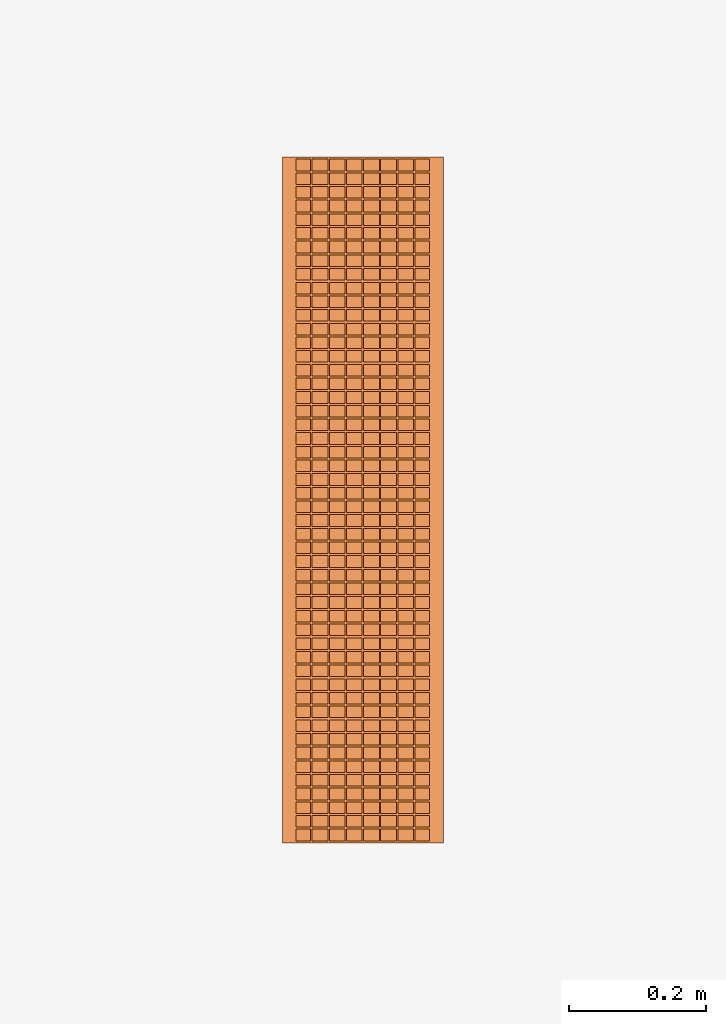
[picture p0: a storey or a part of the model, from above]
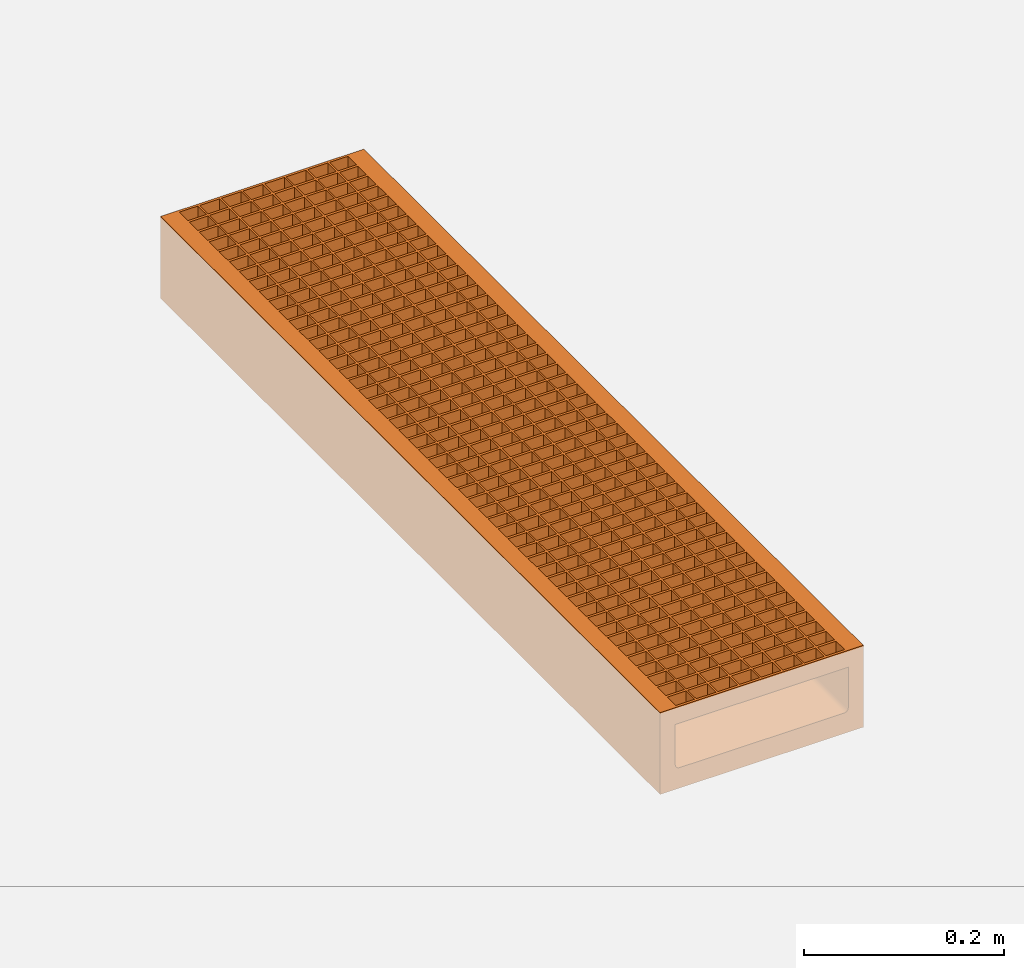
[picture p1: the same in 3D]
Properties of the parts of a building model (IFC2X3)

# File
Description: ViewDefinition [CoordinationView]
File name: 24216 - No 0100 Shallow Depth Channel - 1000mm LG - Invert Depth 75mm.ifc
Time: 2013-10-16T12:50:39
Written by: Autodesk Revit 2013
Made in: 20120221_2030(x64)

# IfcProject, Project Number
LongName: Project Name; Phase: Project Status

# IfcSite, Default
RefLatitude: 42, 21, 30, 344238; RefLongitude: -71, -3, -35, -194702; RefElevation: 0 mm

# IfcBuilding
Pset_BuildingCommon - NumberOfStoreys: 1
Other - Client Name: Owner; Project Number: Project Number; Project Address: ## Street City, State Zip; Project Name: Project Name; Project Issue Date: Issue Date; Project Status: Project Status

# IfcBuildingStorey, Level 1
LongName: Level 1; Elevation: 0 mm
Constraints - Elevation Base: 0; Elevation: 0 mm
Graphics - Line Pattern: Center; Color: 0; Symbol: M_Level Head - Circle: M_Level Head - Circle; Symbol at End 2 Default: yes; Line Weight: 1; Symbol at End 1 Default: no
Identity Data - Structural: no; Building Story: yes; Name: Level 1
Dimensions - Computation Height: 0 mm

# IfcBuildingElementProxy: 24216 - No 0100 Shallow Depth Channel - 1000mm LG - Invert Depth 75mm, Civil-Drainage-Channel-ACO-MultiDrain-M200DS-Channel-System:24216 - No 0100 Shallow Depth Channel - 1000mm LG - Invert Depth 75mm:24216 - No 0100 Shallow Depth Channel - 1000mm LG - Invert Depth 75mm:1152340
In: Level 1
Material: Vienite® Synthetic Resin Concrete
Constraints - Moves With Nearby Elements: no; Level: Level: Level 1
Phasing - Phase Created: New Construction
Construction - 23219 - Universal Endcap (Male End): no; 13448 - Grating - Mesh - Stainless Steel - 1000mm Long: no; 23219 - Universal Endcap (Female End): no; 13449 - Grating - Mesh - Stainless Steel - 500mm Long: no; Shallow Depth Channel with seal: no; Shallow Depth Channel: yes; Constant Depth Channel_500: no; Constant Depth Channel_1000: no; 23410_Sump Unit: no; Grating_1000mm: yes; Grating_500mm: no
Dimensions - Volume: 9511854 mm3; Custom_Value_Length: 0 mm; Length: 1000 mm; EndCap Position: 1000 mm; FloorCut_Length: -1000 mm; FloorCut_Width: 235 mm; Depth: 365 mm; FloorCut_Depth: 100 mm; FloorCut_HorPosition: 117.5 mm; EndCap_Height: 100 mm; InvDepth: 240 mm
Pset_BuildingElementProxyCommon - Reference: 24216 - No 0100 Shallow Depth Channel - 1000mm LG - Invert Depth 75mm
Data - Invert Depth: 75mm; Hydraulic Performance: http://www.aco.co.uk/download.php?id=173; Concrete Surround Volume - Load Class D 400 - Concrete Pavement: 0.17m³/m; Load Class: A 15 - D 400; Installation - Concrete Grade: Refer to brochure; Product Weight: 19.4 Kg; Product Standard: BS EN 1433:2002, CE marked; Concrete Surround Volume - Load Class A 15 - Concrete Pavement: 0.06m³/m; Channel C.S.A: 0.01m²; ACO Hydraulic Design Software: http://www.acodesign.co.uk; Concrete Surround Volume - Load Class B 125 - C 250 - Concrete Pavement: 0.11m³/m; Product Dimensions: 1000mm x 235mm x 100mm (LxWxH)
Identity Data - Watermark 1: This file is the property of ACO Technologies PLC; Maintenance guidelines: http://www.aco.co.uk/download.php?id=173; Installation guidelines: http://www.aco.co.uk/download.php?id=173; Assembly Description: Rain Water Drainage; URL: www.aco.co.uk; Assembly Code: D2040; Address: ACO Business Park, Hitchin Road, Shefford, Bedfordshire, United Kingdom SG17 5TE; e-mail Technical: technical@aco.co.uk; Product Page URL: http://www.aco.co.uk/product_detail.php?id=15; Telephone: +44 (0)1462 816666; Product brochure: http://www.aco.co.uk/download.php?id=173; Manufacturer: ACO Technologies plc - ACO Water Management Division; Type Comments: ACO MultiDrain M200DS 0100 Shallow Constant Depth Channel 1000mm Long; Watermark 2: This file is water marked and users are prohibited to reproduce, adapt, distribute this information; Cost: 0; Fax: +44 (0)1462 815895; e-mail Sales: customersupport@aco.co.uk; Model Description: Channel drainage system; Watermarked By: www.aco.co.uk; OmniClass Title: Rainwater Removal; OmniClass Number: 23.70.50.24; Product Code: 24216; Price: POA - contact ACO; Model: ACO MultiDrain MD - M200DS; Watermarked With: BIM Manager Premium Suite
General - TagNumber: 0; SerialNumber: 0
Materials and Finishes - Channel Colour: Brown; Edge Rail Material: Stainless Steel Grade 304; Channel Material: Vienite® Synthetic Resin Concrete; Edge Rail Colour: Self
Green Building Properties - Edge Rail Recycled Material Content: Between 40% - 90%; Channel Recycled Material Content: 20% minimum; Edge Rail Recyclable: Fully recyclable; Channel Recyclable: Fully recyclable
Other - Revision: 1; CreatedBy: www.aco.co.uk
Model Properties - End Cap Product code 23219: No 306 Universal End Cap - 235mm wide x 365mm long - Spigot Ø160mm x 75mm long - Silver - Polypropylene - 0.4kg; Grating Product code 13448: Load Class C250 - Mesh Stainless Steel Grade 304 13448DL 1000mm long - 23x17mm slot - Intake area 154100mm²/m - 12.0kg; Grating Product code 13449: Load Class C250 - Mesh Stainless Steel Grade 304 13449DL 500mm long - 23x17mm slot - Intake area 154100mm²/m - 6.0kg

# IfcOpeningElement: Recess
In: Level 1
Dimensions - Perimeter: 20000 mm; Volume: 9976500000 mm3; Thickness: 400 mm; Area: 25000000 mm2
Constraints - Room Bounding: yes; Related to Mass: no; Height Offset From Level: 0 mm; Level: Level: Level 1
Phasing - Phase Created: New Construction
Structural - Enable Analytical Model: no; Structural: no
Analytical Properties - Heat Transfer Coefficient (U): 2.0925; Thermal mass: 543920; Thermal Resistance (R): 0.477897; Absorptance: 0.1; Roughness: 1
Construction - Function: 0; Default Thickness: 400 mm
Materials and Finishes - Structural Material: Earth
Graphics - Coarse Scale Fill Color: 0

# IfcSlab: Floor:Generic Floor - 400mm, Floor:Generic Floor - 400mm:193825
In: Level 1
PredefinedType: FLOOR; Material: Earth 400 mm
Dimensions - Perimeter: 20000 mm; Volume: 9976500000 mm3; Thickness: 400 mm; Area: 25000000 mm2
Constraints - Room Bounding: yes; Related to Mass: no; Height Offset From Level: 0 mm; Level: Level: Level 1
Phasing - Phase Created: New Construction
Structural - Enable Analytical Model: no; Structural: no
Pset_SlabCommon - Reference: Generic Floor - 400mm; IsExternal: no; LoadBearing: yes
Analytical Properties - Heat Transfer Coefficient (U): 2.0925; Thermal mass: 543920; Thermal Resistance (R): 0.477897; Absorptance: 0.1; Roughness: 1
Construction - Function: 0; Default Thickness: 400 mm
Materials and Finishes - Structural Material: Earth
Graphics - Coarse Scale Fill Color: 0
